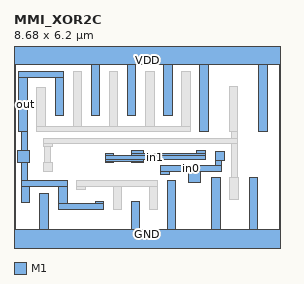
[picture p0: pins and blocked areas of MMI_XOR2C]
MACRO MMI_XOR2C
	CLASS CORE ;
	FOREIGN MMI_XOR2C 0 0 ;
	SIZE 8.68 BY 6.2 ;
	SYMMETRY X Y ;
	SITE CORE1 ;
	PIN out
		DIRECTION output ;
		USE SIGNAL ;
		PORT
			LAYER M1 ;
			RECT 0.15 5.38 1.62 5.575 ;
			LAYER M1 ;
			RECT 0.16 3.59 0.44 5.38 ;
			LAYER M1 ;
			RECT 1.34 4.12 1.62 5.38 ;
			LAYER M1 ;
			RECT 0.24 2.98 0.43 3.59 ;
			LAYER M1 ;
			RECT 0.12 2.6 0.5 2.98 ;
			LAYER M1 ;
			RECT 0.24 2.005 0.43 2.6 ;
			LAYER M1 ;
			RECT 0.24 1.81 1.745 2.005 ;
			LAYER M1 ;
			RECT 0.24 1.305 0.52 1.81 ;
			LAYER M1 ;
			RECT 1.465 1.245 1.745 1.81 ;
			LAYER M1 ;
			RECT 2.645 1.245 2.925 1.33 ;
			LAYER M1 ;
			RECT 1.455 1.05 2.925 1.245 ;
		END
		AntennaDiffArea 2.94525 ;
	END out
	PIN in1
		DIRECTION input ;
		USE SIGNAL ;
		PORT
			LAYER M1 ;
			RECT 3.84 2.885 4.22 2.98 ;
			LAYER M1 ;
			RECT 5.96 2.885 6.24 2.975 ;
			LAYER M1 ;
			RECT 2.98 2.83 3.26 2.875 ;
			LAYER M1 ;
			RECT 3.84 2.83 6.24 2.885 ;
			LAYER M1 ;
			RECT 2.98 2.695 6.24 2.83 ;
			LAYER M1 ;
			RECT 2.98 2.64 4.22 2.695 ;
			LAYER M1 ;
			RECT 2.98 2.595 3.26 2.64 ;
			LAYER M1 ;
			RECT 3.84 2.6 4.22 2.64 ;
		END
		AntennaGateArea 1.9635 ;
	END in1
	PIN GND
		DIRECTION inout ;
		USE GROUND ;
		PORT
			LAYER M1 ;
			RECT 0.83 0.42 1.11 1.585 ;
			LAYER M1 ;
			RECT 3.825 0.42 4.105 1.33 ;
			LAYER M1 ;
			RECT 5.005 0.42 5.285 2.005 ;
			LAYER M1 ;
			RECT 6.445 0.42 6.725 2.095 ;
			LAYER M1 ;
			RECT 7.67 0.42 7.95 2.095 ;
			LAYER M1 ;
			RECT 0 -0.42 8.68 0.42 ;
		END
	END GND
	PIN VDD
		DIRECTION inout ;
		USE POWER ;
		PORT
			LAYER M1 ;
			RECT 0 5.78 8.68 6.62 ;
			LAYER M1 ;
			RECT 2.52 4.12 2.8 5.78 ;
			LAYER M1 ;
			RECT 3.7 4.12 3.98 5.78 ;
			LAYER M1 ;
			RECT 4.88 4.12 5.16 5.78 ;
			LAYER M1 ;
			RECT 6.06 3.59 6.34 5.78 ;
			LAYER M1 ;
			RECT 7.98 3.59 8.26 5.78 ;
		END
	END VDD
	PIN in0
		DIRECTION input ;
		USE SIGNAL ;
		PORT
			LAYER M1 ;
			RECT 6.59 2.66 6.87 2.94 ;
			LAYER M1 ;
			RECT 6.59 2.49 6.785 2.66 ;
			LAYER M1 ;
			RECT 4.78 2.3 6.785 2.49 ;
			LAYER M1 ;
			RECT 4.78 2.21 5.06 2.3 ;
			LAYER M1 ;
			RECT 5.69 1.95 6.08 2.3 ;
		END
		AntennaGateArea 1.9635 ;
	END in0
	OBS
		LAYER M1 ;
		RECT 0.75 3.78 1.03 5.04 ;
		LAYER M1 ;
		RECT 1.93 3.78 2.21 5.575 ;
		LAYER M1 ;
		RECT 3.11 3.78 3.39 5.575 ;
		LAYER M1 ;
		RECT 4.29 3.78 4.57 5.575 ;
		LAYER M1 ;
		RECT 5.47 3.78 5.75 5.575 ;
		LAYER M1 ;
		RECT 0.75 3.59 5.75 3.78 ;
		LAYER M1 ;
		RECT 7.02 3.59 7.3 5.06 ;
		LAYER M1 ;
		RECT 7.105 3.39 7.3 3.59 ;
		LAYER M1 ;
		RECT 0.96 3.2 7.3 3.39 ;
		LAYER M1 ;
		RECT 0.96 3.11 1.24 3.2 ;
		LAYER M1 ;
		RECT 1 2.595 1.195 3.11 ;
		LAYER M1 ;
		RECT 0.96 2.315 1.24 2.595 ;
		LAYER M1 ;
		RECT 2.055 1.815 4.695 2.01 ;
		LAYER M1 ;
		RECT 2.055 1.72 2.335 1.815 ;
		LAYER M1 ;
		RECT 3.235 1.05 3.515 1.815 ;
		LAYER M1 ;
		RECT 4.415 1.05 4.695 1.815 ;
		LAYER M1 ;
		RECT 7.105 2.095 7.3 3.2 ;
		LAYER M1 ;
		RECT 7.035 1.395 7.315 2.095 ;
	END
END MMI_XOR2C
